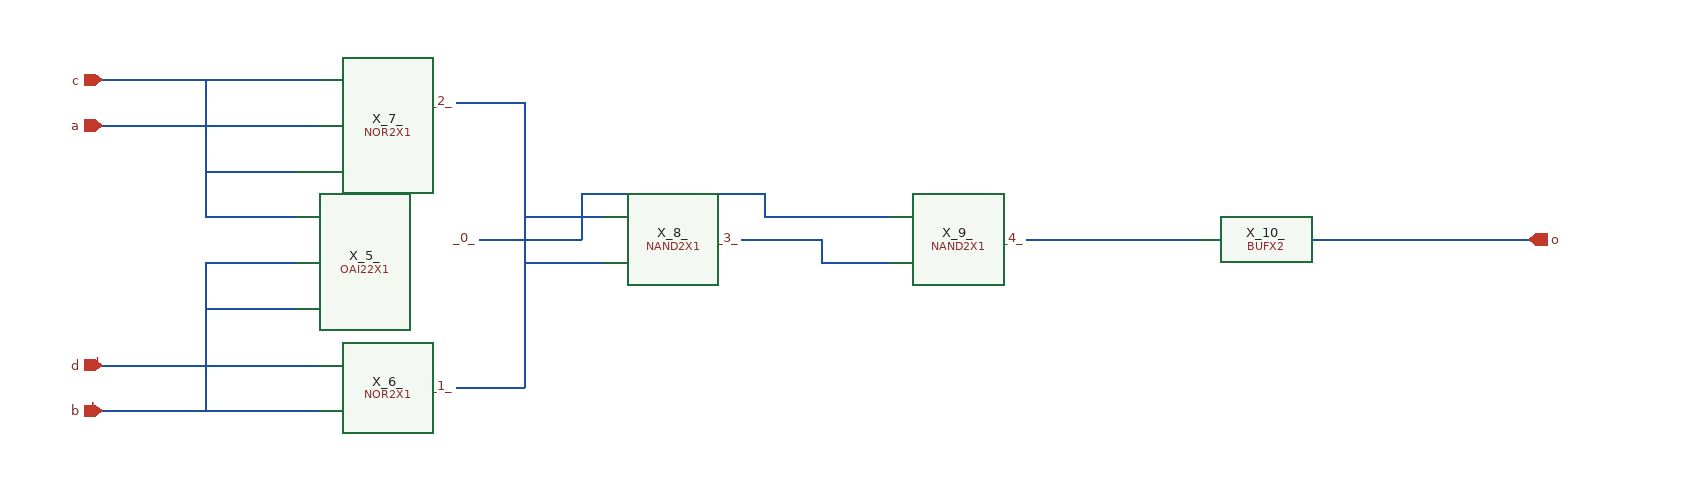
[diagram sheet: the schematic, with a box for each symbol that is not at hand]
v {xschem version=2.9.7 file_version=1.1}
G {}
V {}
S {}
E {}
N 250 520 440 520 {lab=a}
C {devices/lab_wire.sym} 250 520 0 0 {lab=a}
N 250 520 340 520 {lab=a}
N 340 520 340 600 {lab=a}
N 340 600 420 600 {lab=a}
C {devices/lab_wire.sym} 250 520 0 0 {lab=a}
N 560 500 620 500 {lab=_2_}
N 620 500 620 640 {lab=_2_}
N 620 640 690 640 {lab=_2_}
C {devices/lab_wire.sym} 560 500 0 0 {lab=_2_}
N 250 480 440 480 {lab=c}
C {devices/lab_wire.sym} 250 480 0 0 {lab=c}
N 250 480 340 480 {lab=c}
N 340 480 340 560 {lab=c}
N 340 560 420 560 {lab=c}
C {devices/lab_wire.sym} 250 480 0 0 {lab=c}
N 1060 620 1210 620 {lab=_4_}
C {devices/lab_wire.sym} 1060 620 0 0 {lab=_4_}
N 1290 620 1500 620 {lab=o}
C {devices/lab_wire.sym} 1290 620 0 0 {lab=o}
N 580 620 670 620 {lab=_0_}
N 670 620 670 580 {lab=_0_}
N 670 580 830 580 {lab=_0_}
N 830 580 830 600 {lab=_0_}
N 830 600 940 600 {lab=_0_}
C {devices/lab_wire.sym} 580 620 0 0 {lab=_0_}
N 810 620 880 620 {lab=_3_}
N 880 620 880 640 {lab=_3_}
N 880 640 940 640 {lab=_3_}
C {devices/lab_wire.sym} 810 620 0 0 {lab=_3_}
N 250 770 440 770 {lab=b}
C {devices/lab_wire.sym} 250 770 0 0 {lab=b}
N 250 770 340 770 {lab=b}
N 340 770 340 680 {lab=b}
N 340 680 420 680 {lab=b}
C {devices/lab_wire.sym} 250 770 0 0 {lab=b}
N 560 750 620 750 {lab=_1_}
N 620 750 620 600 {lab=_1_}
N 620 600 690 600 {lab=_1_}
C {devices/lab_wire.sym} 560 750 0 0 {lab=_1_}
N 250 730 440 730 {lab=d}
C {devices/lab_wire.sym} 250 730 0 0 {lab=d}
N 250 730 340 730 {lab=d}
N 340 730 340 640 {lab=d}
N 340 640 420 640 {lab=d}
C {devices/lab_wire.sym} 250 730 0 0 {lab=d}
C {osu035_xschem/NOR2X1.sym} 500 500 0 0 {name=X_7_ VCCPIN=vcc VSSPIN=gnd}
C {osu035_xschem/BUFX2.sym} 1250 620 0 0 {name=X_10_ VCCPIN=vcc VSSPIN=gnd}
C {osu035_xschem/NAND2X1.sym} 1000 620 0 0 {name=X_9_ VCCPIN=vcc VSSPIN=gnd}
C {osu035_xschem/NOR2X1.sym} 500 750 0 0 {name=X_6_ VCCPIN=vcc VSSPIN=gnd}
C {osu035_xschem/NAND2X1.sym} 750 620 0 0 {name=X_8_ VCCPIN=vcc VSSPIN=gnd}
C {osu035_xschem/OAI22X1.sym} 500 620 0 0 {name=X_5_ VCCPIN=vcc VSSPIN=gnd}
C {devices/ipin.sym} 250 520 0 0 {lab=a}
C {devices/ipin.sym} 250 770 0 0 {lab=b}
C {devices/ipin.sym} 250 480 0 0 {lab=c}
C {devices/ipin.sym} 250 730 0 0 {lab=d}
C {devices/opin.sym} 1500 620 0 0 {lab=o}
